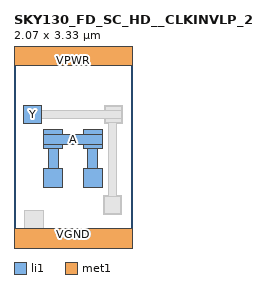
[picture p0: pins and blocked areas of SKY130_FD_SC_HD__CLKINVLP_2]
MACRO SKY130_FD_SC_HD__CLKINVLP_2
 CLASS CORE ;
 FOREIGN SKY130_FD_SC_HD__CLKINVLP_2 0 0 ;
 SIZE 2.07 BY 3.33 ;
 ORIGIN 0 0 ;
 SYMMETRY X Y R90 ;
 SITE unit ;
  PIN VPWR
   DIRECTION INOUT ;
   USE POWER ;
   SHAPE ABUTMENT ;
    PORT
     CLASS CORE ;
       LAYER li1 ;
        RECT 0.00000000 3.09000000 2.07000000 3.57000000 ;
       LAYER met1 ;
        RECT 0.00000000 3.09000000 2.07000000 3.57000000 ;
    END
  END VPWR

  PIN VGND
   DIRECTION INOUT ;
   USE POWER ;
   SHAPE ABUTMENT ;
    PORT
     CLASS CORE ;
       LAYER li1 ;
        RECT 0.00000000 -0.24000000 2.07000000 0.24000000 ;
       LAYER met1 ;
        RECT 0.00000000 -0.24000000 2.07000000 0.24000000 ;
    END
  END VGND

  PIN Y
   DIRECTION INOUT ;
   USE SIGNAL ;
   SHAPE ABUTMENT ;
    PORT
     CLASS CORE ;
       LAYER li1 ;
        RECT 0.16000000 2.07000000 0.49000000 2.40000000 ;
    END
  END Y

  PIN A
   DIRECTION INOUT ;
   USE SIGNAL ;
   SHAPE ABUTMENT ;
    PORT
     CLASS CORE ;
       LAYER li1 ;
        RECT 0.52500000 0.96000000 0.85500000 1.29000000 ;
        RECT 1.21500000 0.96000000 1.54500000 1.29000000 ;
        RECT 0.60500000 1.29000000 0.77500000 1.63500000 ;
        RECT 1.29500000 1.29000000 1.46500000 1.63500000 ;
        RECT 0.52500000 1.63500000 0.85500000 1.71500000 ;
        RECT 1.21500000 1.63500000 1.54500000 1.71500000 ;
        RECT 0.52500000 1.71500000 1.54500000 1.88500000 ;
        RECT 0.52500000 1.88500000 0.85500000 1.96500000 ;
        RECT 1.21500000 1.88500000 1.54500000 1.96500000 ;
    END
  END A

 OBS
    LAYER polycont ;
     RECT 0.60500000 1.04000000 0.77500000 1.21000000 ;
     RECT 1.29500000 1.04000000 1.46500000 1.21000000 ;
     RECT 0.60500000 1.71500000 0.77500000 1.88500000 ;
     RECT 1.29500000 1.71500000 1.46500000 1.88500000 ;

    LAYER pdiffc ;
     RECT 0.24000000 2.15000000 0.41000000 2.32000000 ;
     RECT 1.66000000 2.15000000 1.83000000 2.32000000 ;

    LAYER ndiffc ;
     RECT 1.64000000 0.56000000 1.81000000 0.73000000 ;
     RECT 0.26000000 0.30000000 0.43000000 0.47000000 ;

    LAYER li1 ;
     RECT 1.56000000 0.48000000 1.89000000 0.81000000 ;
     RECT 0.16000000 2.07000000 0.49000000 2.40000000 ;
     RECT 1.58000000 2.07000000 1.91000000 2.40000000 ;
     RECT 0.00000000 3.09000000 2.07000000 3.57000000 ;
     RECT 0.00000000 -0.24000000 2.07000000 0.24000000 ;
     RECT 0.18000000 0.24000000 0.51000000 0.55000000 ;
     RECT 0.52500000 0.96000000 0.85500000 1.29000000 ;
     RECT 1.21500000 0.96000000 1.54500000 1.29000000 ;
     RECT 0.60500000 1.29000000 0.77500000 1.63500000 ;
     RECT 1.29500000 1.29000000 1.46500000 1.63500000 ;
     RECT 0.52500000 1.63500000 0.85500000 1.71500000 ;
     RECT 1.21500000 1.63500000 1.54500000 1.71500000 ;
     RECT 0.52500000 1.71500000 1.54500000 1.88500000 ;
     RECT 0.52500000 1.88500000 0.85500000 1.96500000 ;
     RECT 1.21500000 1.88500000 1.54500000 1.96500000 ;

    LAYER viali ;
     RECT 1.64000000 0.56000000 1.81000000 0.73000000 ;
     RECT 0.24000000 2.15000000 0.41000000 2.32000000 ;
     RECT 1.66000000 2.15000000 1.83000000 2.32000000 ;
     RECT 0.14500000 3.24500000 0.31500000 3.41500000 ;
     RECT 0.26000000 -0.08500000 0.43000000 0.08500000 ;

    LAYER met1 ;
     RECT 1.58000000 0.50000000 1.87000000 0.79000000 ;
     RECT 1.65500000 0.79000000 1.79500000 2.09000000 ;
     RECT 0.18000000 2.09000000 0.47000000 2.16500000 ;
     RECT 1.60000000 2.09000000 1.89000000 2.16500000 ;
     RECT 0.18000000 2.16500000 1.89000000 2.30500000 ;
     RECT 0.18000000 2.30500000 0.47000000 2.38000000 ;
     RECT 1.60000000 2.30500000 1.89000000 2.38000000 ;
     RECT 0.00000000 3.09000000 2.07000000 3.57000000 ;
     RECT 0.00000000 -0.24000000 2.07000000 0.24000000 ;

    LAYER via ;


    LAYER met2 ;


    LAYER via2 ;


    LAYER met3 ;


 END
END SKY130_FD_SC_HD__CLKINVLP_2
